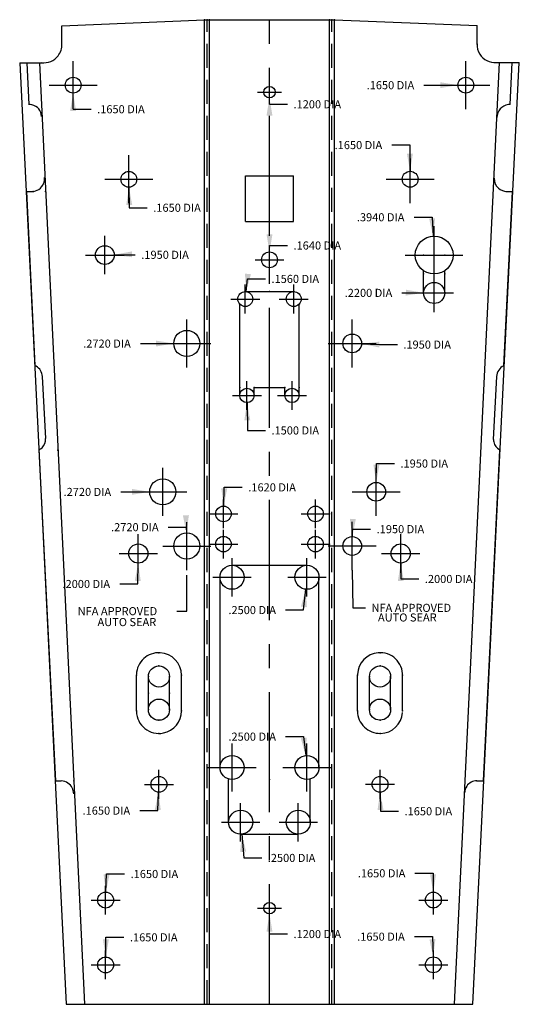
# Model space of a CAD drawing. Extents: x 2.7 to 7.9, y -3.4 to 6.9.
import ezdxf

# ---------------------------------------------------------------- set-up
doc = ezdxf.new("R2010")
doc.units = 0
doc.header["$MEASUREMENT"] = 0
doc.linetypes.add('CENTER', pattern=[2, 1.25, -0.25, 0.25, -0.25])
doc.linetypes.add('HIDDEN', pattern=[0.375, 0.25, -0.125])
doc.layers.add('DEFAULT', color=7, linetype='CONTINUOUS')
doc.styles.add('ARIAL', font='ARIAL.TTF')

msp = doc.modelspace()

# ---------------------------------------------------------------- linework, layer by layer
at = {"layer": 'DEFAULT'}
for p, q in [((3.0926, 6.8103), (4.5766, 6.8723)), ((4.577, 6.8728), (4.627, 6.8728)), ((4.577, -3.3772), (4.577, 6.8728)), ((4.627, 6.8728), (5.252, 6.8728)), ((4.627, -3.3772), (4.627, 6.8728)), ((5.252, 6.8728), (5.877, 6.8728)), ((5.877, 6.8728), (5.927, 6.8728)), ((5.877, -3.3772), (5.877, 6.8728)), ((5.927, -3.3772), (5.927, 6.8728)), ((5.9276, 6.8727), (7.4116, 6.8107)), ((3.0926, 6.6128), (3.0926, 6.8103)), ((7.4116, 6.6132), (7.4116, 6.8107)), ((2.6526, 6.4253), (3.1366, -3.3777)), ((2.6526, 6.4253), (2.7276, 6.4253)), ((2.7276, 6.4253), (2.8576, 6.4253)), ((2.7276, 6.4253), (2.7488, 5.9893)), ((2.8576, 6.4253), (3.3266, -3.3777)), ((2.8576, 6.4253), (2.9052, 6.4253)), ((3.2086, 6.1913), (3.2086, 6.4413)), ((7.1776, -3.3773), (7.6466, 6.4257)), ((7.2956, 6.1917), (7.2956, 6.4417)), ((7.3676, -3.3773), (7.8516, 6.4257)), ((7.599, 6.4257), (7.6466, 6.4257)), ((7.6466, 6.4257), (7.7766, 6.4257)), ((7.757, 5.9891), (7.7766, 6.4257)), ((7.7766, 6.4257), (7.8516, 6.4257)), ((2.9586, 6.1913), (3.2086, 6.1913)), ((3.2086, 6.1913), (3.4586, 6.1913)), ((3.2086, 5.9413), (3.2086, 6.1913)), ((5.252, 6.1178), (5.252, 6.2428)), ((6.8581, 6.1917), (7.0456, 6.1917)), ((7.0456, 6.1917), (7.2131, 6.1917)), ((7.0456, 6.1917), (7.2956, 6.1917)), ((7.2956, 5.9417), (7.2956, 6.1917)), ((7.2956, 6.1917), (7.5456, 6.1917)), ((3.2086, 5.9413), (3.2086, 6.1088)), ((5.127, 6.1178), (5.252, 6.1178)), ((5.2395, 6.1178), (5.252, 6.1178)), ((5.252, 5.9928), (5.252, 6.1178)), ((5.252, 6.1178), (5.377, 6.1178)), ((5.252, 5.9928), (5.252, 6.0578)), ((5.252, 5.9928), (5.4395, 5.9928)), ((3.2086, 5.9413), (3.3961, 5.9413)), ((6.525, 5.5684), (6.7125, 5.5684)), ((6.7125, 5.5684), (6.7149, 5.2941)), ((3.7886, 5.2113), (3.7886, 5.4613)), ((6.7156, 5.2117), (6.7156, 5.4617)), ((5.002, 5.2478), (5.252, 5.2478)), ((5.002, 4.7728), (5.002, 5.2478)), ((5.252, 5.2478), (5.502, 5.2478)), ((5.502, 4.7728), (5.502, 5.2478)), ((3.5386, 5.2113), (3.7886, 5.2113)), ((3.7886, 4.9613), (3.7886, 5.2113)), ((3.7886, 5.2113), (4.0386, 5.2113)), ((3.7897, 5.1289), (3.7927, 4.9157)), ((6.4656, 5.2117), (6.7156, 5.2117)), ((6.7156, 4.9617), (6.7156, 5.2117)), ((6.7156, 5.2117), (6.9656, 5.2117)), ((2.7221, 5.0827), (2.7939, 5.0827)), ((2.7221, 5.0827), (2.8089, 3.272)), ((7.6908, 3.2701), (7.7806, 5.0827)), ((7.7103, 5.0837), (7.7806, 5.0827)), ((3.7927, 4.9157), (3.9802, 4.9157)), ((5.002, 4.7728), (5.252, 4.7728)), ((5.252, 4.7728), (5.502, 4.7728)), ((6.7563, 4.8167), (6.9438, 4.8167)), ((6.9438, 4.8167), (6.9548, 4.6193)), ((6.9656, 4.4227), (6.9656, 4.7227)), ((3.5386, 4.4223), (3.5386, 4.6223)), ((5.252, 4.4548), (5.252, 4.5228)), ((5.252, 4.5228), (5.4395, 4.5228)), ((5.252, 4.3728), (5.252, 4.5228)), ((3.3386, 4.4223), (3.5386, 4.4223)), ((3.5386, 4.2223), (3.5386, 4.4223)), ((3.5386, 4.4223), (3.7386, 4.4223)), ((3.636, 4.4249), (3.6679, 4.4258)), ((3.6679, 4.4258), (3.8554, 4.4258)), ((6.6656, 4.4227), (6.9656, 4.4227)), ((6.9656, 4.4227), (7.2656, 4.4227)), ((6.9656, 4.1227), (6.9656, 4.4227)), ((5.102, 4.3728), (5.252, 4.3728)), ((5.252, 4.2228), (5.252, 4.3728)), ((5.252, 4.3728), (5.402, 4.3728)), ((6.8556, 4.0277), (6.8556, 4.2592)), ((6.9656, 4.0277), (6.9656, 4.2277)), ((7.0756, 4.0277), (7.0756, 4.2592)), ((5, 3.9648), (5, 4.1148)), ((5.0083, 4.0423), (5.0226, 4.1751)), ((5.0226, 4.1751), (5.2101, 4.1751)), ((5.504, 3.9648), (5.504, 4.1148)), ((5, 4.0428), (5.252, 4.0428)), ((5.252, 4.0428), (5.504, 4.0428)), ((6.6293, 4.0296), (6.8168, 4.0296)), ((6.7656, 4.0277), (6.9656, 4.0277)), ((6.8168, 4.0296), (6.8557, 4.0291)), ((6.9656, 3.8277), (6.9656, 4.0277)), ((6.9656, 4.0277), (7.1656, 4.0277)), ((4.85, 3.9648), (5, 3.9648)), ((4.9425, 3.0428), (4.9425, 3.912)), ((5, 3.8148), (5, 3.9648)), ((5, 3.9648), (5.15, 3.9648)), ((5.354, 3.9648), (5.504, 3.9648)), ((5.504, 3.8148), (5.504, 3.9648)), ((5.504, 3.9648), (5.654, 3.9648)), ((5.5615, 3.0428), (5.5615, 3.912)), ((4.3916, 3.5023), (4.3916, 3.7523)), ((6.1126, 3.5027), (6.1126, 3.7527)), ((3.9085, 3.5013), (4.096, 3.5013)), ((4.096, 3.5013), (4.2557, 3.5019)), ((4.1416, 3.5023), (4.3916, 3.5023)), ((4.3916, 3.2523), (4.3916, 3.5023)), ((4.3916, 3.5023), (4.6416, 3.5023)), ((5.8626, 3.5027), (6.1126, 3.5027)), ((6.1126, 3.2527), (6.1126, 3.5027)), ((6.1126, 3.5027), (6.3626, 3.5027)), ((6.21, 3.4987), (6.3951, 3.4911)), ((6.3951, 3.4911), (6.5826, 3.4911)), ((2.8881, 3.1583), (2.9216, 2.5121)), ((5.0175, 2.9608), (5.0175, 3.1108)), ((5.4865, 2.9608), (5.4865, 3.1108)), ((7.5824, 2.5037), (7.6161, 3.1578)), ((4.9425, 2.9608), (4.9425, 3.0428)), ((5.0925, 2.9608), (5.0925, 3.0428)), ((5.0925, 3.0428), (5.4115, 3.0428)), ((5.4115, 2.9608), (5.4115, 3.0428)), ((5.5615, 2.9608), (5.5615, 3.0428)), ((4.8675, 2.9608), (5.0175, 2.9608)), ((5.0175, 2.8108), (5.0175, 2.9608)), ((5.0175, 2.9608), (5.1675, 2.9608)), ((5.0185, 2.8859), (5.0226, 2.5974)), ((5.3365, 2.9608), (5.4865, 2.9608)), ((5.4865, 2.8108), (5.4865, 2.9608)), ((5.4865, 2.9608), (5.6365, 2.9608)), ((5.0226, 2.5974), (5.2101, 2.5974)), ((2.8521, 2.3937), (3.0251, -1.0523)), ((7.4776, -1.0523), (7.6476, 2.3907)), ((4.1416, 1.9573), (4.1416, 2.2073)), ((6.3626, 1.9577), (6.3626, 2.2077)), ((6.3633, 2.0551), (6.3648, 2.2528)), ((6.3648, 2.2528), (6.5523, 2.2528)), ((3.7041, 1.9573), (3.8916, 1.9573)), ((3.8916, 1.9573), (4.0056, 1.9573)), ((3.8916, 1.9573), (4.1416, 1.9573)), ((4.1416, 1.7073), (4.1416, 1.9573)), ((4.1416, 1.9573), (4.3916, 1.9573)), ((4.7755, 1.8087), (4.7816, 2.0047)), ((4.7816, 2.0047), (4.9691, 2.0047)), ((6.1126, 1.9577), (6.3626, 1.9577)), ((6.3626, 1.7077), (6.3626, 1.9577)), ((6.3626, 1.9577), (6.6126, 1.9577)), ((4.773, 1.7278), (4.773, 1.8778)), ((5.731, 1.7278), (5.731, 1.8778)), ((4.3916, 1.3933), (4.3916, 1.6433)), ((4.623, 1.7278), (4.773, 1.7278)), ((4.773, 1.5778), (4.773, 1.7278)), ((4.773, 1.7278), (4.923, 1.7278)), ((5.581, 1.7278), (5.731, 1.7278)), ((5.731, 1.5778), (5.731, 1.7278)), ((5.731, 1.7278), (5.881, 1.7278)), ((6.1126, 1.3937), (6.1126, 1.6437)), ((4.1983, 1.5905), (4.3858, 1.5905)), ((4.3858, 1.5905), (4.3877, 1.5292)), ((4.773, 1.4128), (4.773, 1.5628)), ((5.731, 1.4128), (5.731, 1.5628)), ((6.1149, 1.4911), (6.1169, 1.5694)), ((6.1169, 1.5694), (6.3044, 1.5694)), ((3.8866, 1.3153), (3.8866, 1.5153)), ((3.8866, 1.3153), (3.8866, 1.4653)), ((6.6176, 1.3157), (6.6176, 1.5157)), ((3.8866, 1.3153), (3.8866, 1.4153)), ((4.1416, 1.3933), (4.3916, 1.3933)), ((4.3916, 1.1433), (4.3916, 1.3933)), ((4.3916, 1.3933), (4.6416, 1.3933)), ((4.623, 1.4128), (4.773, 1.4128)), ((4.773, 1.2628), (4.773, 1.4128)), ((4.773, 1.4128), (4.923, 1.4128)), ((5.581, 1.4128), (5.731, 1.4128)), ((5.731, 1.2628), (5.731, 1.4128)), ((5.731, 1.4128), (5.881, 1.4128)), ((5.8626, 1.3937), (6.1126, 1.3937)), ((6.1126, 1.3937), (6.3626, 1.3937)), ((6.1126, 1.1437), (6.1126, 1.3937)), ((3.6866, 1.3153), (3.8866, 1.3153)), ((3.8866, 1.1653), (3.8866, 1.3153)), ((3.8866, 1.1153), (3.8866, 1.3153)), ((3.8866, 1.3153), (4.0866, 1.3153)), ((4.862, 1.0678), (4.862, 1.2678)), ((5.642, 1.0678), (5.642, 1.2678)), ((6.4176, 1.3157), (6.6176, 1.3157)), ((6.6176, 1.1157), (6.6176, 1.3157)), ((6.6176, 1.3157), (6.8176, 1.3157)), ((3.8804, 0.9989), (3.8847, 1.2154)), ((4.862, 1.1928), (5.252, 1.1928)), ((5.252, 1.1928), (5.6421, 1.1928)), ((6.1126, 1.1437), (6.1179, 0.7504)), ((6.618, 1.2158), (6.6188, 1.051)), ((4.3926, 0.716), (4.3926, 1.09)), ((4.662, 1.0678), (4.862, 1.0678)), ((4.737, -0.7572), (4.737, 1.0678)), ((4.862, 0.8678), (4.862, 1.0678)), ((4.862, 1.0678), (5.062, 1.0678)), ((5.442, 1.0678), (5.642, 1.0678)), ((5.642, 0.8678), (5.642, 1.0678)), ((5.642, 1.0678), (5.842, 1.0678)), ((5.767, -0.7572), (5.767, 1.0678)), ((6.6188, 1.051), (6.8063, 1.051)), ((3.6929, 0.9989), (3.8804, 0.9989)), ((5.607, 0.7275), (5.6293, 0.9435)), ((5.4195, 0.7275), (5.607, 0.7275)), ((6.1179, 0.7504), (6.2508, 0.7504)), ((4.2866, 0.716), (4.3926, 0.716)), ((3.8666, -0.3227), (3.8666, 0.0472)), ((3.9916, -0.3102), (3.9916, 0.0348)), ((4.2116, -0.3102), (4.2116, 0.0346)), ((4.3366, -0.3227), (4.3366, 0.0472)), ((6.1676, -0.3223), (6.1676, 0.0476)), ((6.2926, -0.3098), (6.2927, 0.035)), ((6.5126, -0.3098), (6.5126, 0.035)), ((6.6376, -0.3223), (6.6376, 0.0477)), ((5.4195, -0.5904), (5.607, -0.5904)), ((5.607, -0.5904), (5.6285, -0.788)), ((4.862, -0.9122), (4.862, -0.6622)), ((5.642, -0.9122), (5.642, -0.6622)), ((4.737, -0.9122), (4.737, -0.7572)), ((5.767, -0.9122), (5.767, -0.7572)), ((4.612, -0.9122), (4.862, -0.9122)), ((4.862, -1.1622), (4.862, -0.9122)), ((4.862, -0.9122), (5.112, -0.9122)), ((5.392, -0.9122), (5.642, -0.9122)), ((5.642, -1.1622), (5.642, -0.9122)), ((5.642, -0.9122), (5.892, -0.9122)), ((4.1016, -1.0877), (4.1016, -0.9377)), ((6.4026, -1.0873), (6.4026, -0.9373)), ((3.0251, -1.0523), (3.0856, -1.0526)), ((3.9516, -1.0877), (4.1016, -1.0877)), ((4.1016, -1.2377), (4.1016, -1.0877)), ((4.1016, -1.0877), (4.2516, -1.0877)), ((4.827, -1.4822), (4.827, -1.0372)), ((5.677, -1.4822), (5.677, -1.0372)), ((6.2526, -1.0873), (6.4026, -1.0873)), ((6.4026, -1.2373), (6.4026, -1.0873)), ((6.4026, -1.0873), (6.5526, -1.0873)), ((7.4076, -1.0523), (7.4776, -1.0523)), ((4.0893, -1.3607), (4.0979, -1.1701)), ((6.4041, -1.1697), (6.4077, -1.3671)), ((4.952, -1.4822), (4.952, -1.2822)), ((5.552, -1.4822), (5.552, -1.2822)), ((3.9018, -1.3607), (4.0893, -1.3607)), ((6.4077, -1.3671), (6.5952, -1.3671)), ((4.752, -1.4822), (4.952, -1.4822)), ((4.952, -1.6822), (4.952, -1.4822)), ((4.952, -1.4822), (5.152, -1.4822)), ((5.352, -1.4822), (5.552, -1.4822)), ((5.552, -1.6822), (5.552, -1.4822)), ((5.552, -1.4822), (5.752, -1.4822)), ((4.952, -1.6072), (5.252, -1.6072)), ((4.9627, -1.6067), (4.9841, -1.853)), ((5.252, -1.6072), (5.552, -1.6072)), ((4.9841, -1.853), (5.1716, -1.853)), ((3.5496, -2.2103), (3.5568, -2.0203)), ((3.5568, -2.0203), (3.7443, -2.0203)), ((6.7661, -2.0131), (6.9536, -2.0131)), ((6.9536, -2.0131), (6.9565, -2.2099)), ((3.5466, -2.2927), (3.5466, -2.1427)), ((6.9576, -2.2923), (6.9576, -2.1423)), ((5.252, -2.3772), (5.252, -2.2522)), ((3.3966, -2.2927), (3.5466, -2.2927)), ((3.5466, -2.4427), (3.5466, -2.2927)), ((3.5466, -2.2927), (3.6966, -2.2927)), ((6.8076, -2.2923), (6.9576, -2.2923)), ((6.9576, -2.4423), (6.9576, -2.2923)), ((6.9576, -2.2923), (7.1076, -2.2923)), ((5.127, -2.3772), (5.252, -2.3772)), ((5.2518, -2.6454), (5.252, -2.4371)), ((5.252, -2.5022), (5.252, -2.3772)), ((5.252, -2.3772), (5.377, -2.3772)), ((5.2518, -2.6454), (5.4393, -2.6454)), ((3.5476, -2.8853), (3.5501, -2.6799)), ((3.5501, -2.6799), (3.7376, -2.6799)), ((6.7594, -2.6727), (6.9469, -2.6727)), ((6.9469, -2.6727), (6.9547, -2.8849)), ((3.5466, -2.9677), (3.5466, -2.8177)), ((6.9576, -2.9673), (6.9576, -2.8173)), ((3.3966, -2.9677), (3.5466, -2.9677)), ((3.5466, -3.1177), (3.5466, -2.9677)), ((3.5466, -2.9677), (3.6966, -2.9677)), ((6.8076, -2.9673), (6.9576, -2.9673)), ((6.9576, -3.1173), (6.9576, -2.9673)), ((6.9576, -2.9673), (7.1076, -2.9673)), ((3.1366, -3.3777), (3.1366, -3.3761)), ((3.1366, -3.3777), (3.3266, -3.3777)), ((3.2116, -3.3777), (3.3266, -3.3777)), ((3.3266, -3.3777), (4.5766, -3.3777)), ((4.577, -3.3772), (4.627, -3.3772)), ((4.627, -3.3772), (5.252, -3.3772)), ((5.252, -3.3772), (5.877, -3.3772)), ((5.877, -3.3772), (5.927, -3.3772)), ((5.9276, -3.3773), (7.1776, -3.3773)), ((7.1776, -3.3773), (7.2926, -3.3773)), ((7.1776, -3.3773), (7.3676, -3.3773))]:
    msp.add_line(p, q, dxfattribs=at)
at = {"layer": 'DEFAULT', "linetype": 'HIDDEN'}
for p, q in [((4.602, -3.3772), (4.602, 6.8728)), ((5.902, -3.3772), (5.902, 6.8728))]:
    msp.add_line(p, q, dxfattribs=at)
at = {"layer": 'DEFAULT', "linetype": 'CENTER'}
msp.add_line((5.252, -3.3772), (5.252, 6.8728), dxfattribs=at)
at = {"layer": 'DEFAULT'}
for centre, radius in [((3.2086, 6.1913), 0.0825), ((7.2956, 6.1917), 0.0825), ((5.252, 6.1178), 0.06), ((3.7886, 5.2113), 0.0825), ((6.7156, 5.2117), 0.0825), ((6.9656, 4.4227), 0.197), ((3.5386, 4.4223), 0.0975), ((5.252, 4.3728), 0.082), ((6.9656, 4.0277), 0.11), ((5, 3.9648), 0.078), ((5.504, 3.9648), 0.078), ((4.3916, 3.5023), 0.136), ((6.1126, 3.5027), 0.0975), ((5.0175, 2.9608), 0.075), ((5.4865, 2.9608), 0.075), ((4.1416, 1.9573), 0.136), ((6.3626, 1.9577), 0.0975), ((4.773, 1.7278), 0.081), ((5.731, 1.7278), 0.081), ((4.3916, 1.3933), 0.136), ((4.773, 1.4128), 0.081), ((5.731, 1.4128), 0.081), ((6.1126, 1.3937), 0.0975), ((3.8866, 1.3153), 0.1), ((6.6176, 1.3157), 0.1), ((4.862, 1.0678), 0.125), ((5.642, 1.0678), 0.125), ((4.1016, 0.0348), 0.11), ((6.4026, 0.0352), 0.11), ((4.1016, -0.3102), 0.11), ((6.4026, -0.3098), 0.11), ((4.862, -0.9122), 0.125), ((5.642, -0.9122), 0.125), ((4.1016, -1.0877), 0.0825), ((6.4026, -1.0873), 0.0825), ((4.952, -1.4822), 0.125), ((5.552, -1.4822), 0.125), ((3.5466, -2.2927), 0.0825), ((6.9576, -2.2923), 0.0825), ((5.252, -2.3772), 0.06), ((3.5466, -2.9677), 0.0825), ((6.9576, -2.9673), 0.0825)]:
    msp.add_circle(centre, radius, dxfattribs=at)
for centre, radius, start, end in [((2.9051, 6.6128), 0.1875, 321.3259, 2.2014), ((7.5991, 6.6132), 0.1875, 177.9513, 211.8498), ((2.9051, 6.6128), 0.1875, 262.4276, 321.3259), ((7.5991, 6.6132), 0.1875, 211.8498, 273.9157), ((2.7538, 5.8643), 0.125, 77.8444, 93.7165), ((2.7538, 5.8643), 0.125, 0.8257, 77.8444), ((7.754, 5.8521), 0.137, 96.7098, 179.4978), ((7.754, 5.8521), 0.137, 88.8283, 96.7098), ((2.7751, 5.2197), 0.137, 336.9168, 4.187), ((2.7751, 5.2197), 0.137, 271.7154, 336.9168), ((7.7276, 5.2197), 0.137, 179.2467, 227.2197), ((7.7276, 5.2197), 0.137, 227.2197, 267.7395), ((2.7632, 3.1557), 0.125, 61.2394, 68.5477), ((2.7632, 3.1557), 0.125, 1.1925, 61.2394), ((7.741, 3.1557), 0.125, 113.6924, 179.0368), ((2.7968, 2.5057), 0.125, 314.7405, 2.9357), ((7.7073, 2.5057), 0.125, 180.9174, 193.4244), ((7.7073, 2.5057), 0.125, 193.4244, 241.6713), ((2.7968, 2.5057), 0.125, 296.2779, 314.7405), ((4.1016, 0.0473), 0.235, 87.1218, 177.4384), ((4.1016, 0.0473), 0.235, 0.3171, 87.1218), ((6.4026, 0.0477), 0.235, 94.6867, 177.7805), ((6.4026, 0.0477), 0.235, 358.7075, 94.6867), ((6.4026, -0.3223), 0.235, 91.0487, 91.0731), ((4.1016, -0.3227), 0.235, 181.4876, 281.3147), ((4.1016, -0.3227), 0.235, 281.3147, 359.6097), ((6.4026, -0.3223), 0.235, 180.7805, 271.0487), ((6.4026, -0.3223), 0.235, 271.0487, 355.6798), ((4.862, -0.7572), 0.125, 40.064, 40.3575), ((3.0781, -1.1893), 0.137, 55.8922, 86.8596), ((3.0781, -1.1893), 0.137, 0.7951, 55.8922), ((7.4076, -1.1773), 0.125, 145.801, 179.1285), ((7.4076, -1.1773), 0.125, 88.349, 145.801)]:
    msp.add_arc(centre, radius, start, end, dxfattribs=at)
at = {"layer": 'DEFAULT', "color": 1}
for p in [(4.577, 6.8728), (4.602, 6.8728), (4.602, 6.8728), (4.627, 6.8728), (5.877, 6.8728), (5.902, 6.8728), (5.927, 6.8728), (3.2086, 6.1913), (7.2956, 6.1917), (5.252, 6.1178), (5.252, 5.2478), (5.252, 5.2478), (3.7886, 5.2113), (6.7156, 5.2117), (2.7939, 5.0827), (2.9221, 5.0827), (5.252, 4.7728), (3.5386, 4.4223), (6.8556, 4.4227), (6.9656, 4.4227), (7.0756, 4.4227), (5.252, 4.3728), (6.8556, 4.2277), (7.0756, 4.2277), (5, 4.0428), (5.252, 4.0428), (5.504, 4.0428), (6.8556, 4.0277), (6.9656, 4.0277), (7.0756, 4.0277), (5, 3.9648), (5.504, 3.9648), (4.3916, 3.5023), (6.1126, 3.5027), (4.9425, 3.0428), (5.0925, 3.0428), (5.252, 3.0428), (5.4115, 3.0428), (5.5615, 3.0428), (4.9425, 2.9608), (5.0175, 2.9608), (5.0925, 2.9608), (5.4115, 2.9608), (5.4865, 2.9608), (5.5615, 2.9608), (3.0501, 2.3907), (4.1416, 1.9573), (6.3626, 1.9577), (4.773, 1.7278), (5.731, 1.7278), (5.877, 1.7278), (4.3916, 1.3933), (4.773, 1.4128), (5.731, 1.4128), (5.877, 1.4128), (5.877, 1.4128), (6.1126, 1.3937), (3.8866, 1.3153), (6.6176, 1.3157), (5.252, 1.1928), (4.862, 1.0678), (5.642, 1.0678), (4.1016, 0.2823), (6.4026, 0.2827), (4.1016, 0.1448), (6.4026, 0.1452), (3.8666, 0.0473), (3.9916, 0.0348), (4.2116, 0.0348), (4.3366, 0.0473), (6.1676, 0.0477), (6.2926, 0.0352), (6.5126, 0.0352), (6.6376, 0.0477), (3.9916, -0.1377), (4.2116, -0.1377), (3.8666, -0.3227), (3.9916, -0.3102), (4.2116, -0.3102), (4.3366, -0.3227), (6.1676, -0.3223), (6.2926, -0.3098), (6.5126, -0.3098), (6.6376, -0.3223), (4.1016, -0.4202), (6.4026, -0.4198), (4.1016, -0.5577), (4.1016, -0.5577), (6.4026, -0.5573), (4.862, -0.9122), (5.642, -0.9122), (3.2151, -1.0523), (4.1016, -1.0877), (5.252, -1.0372), (6.4026, -1.0873), (4.952, -1.4822), (5.552, -1.4822), (5.252, -1.6072), (3.5466, -2.2927), (6.9576, -2.2923), (5.252, -2.3772), (3.5466, -2.9677), (6.9576, -2.9673), (4.577, -3.3772), (4.602, -3.3772), (4.627, -3.3772), (5.252, -3.3772), (5.877, -3.3772), (5.902, -3.3772), (5.927, -3.3772), (7.1776, -3.3773)]:
    msp.add_point(p, dxfattribs=at)
at = {"layer": 'DEFAULT'}
for points in [[(7.0282, 6.1611), (7.0282, 6.2222), (7.2131, 6.1917)], [(3.2396, 5.9239), (3.1775, 5.9239), (3.2086, 6.1088)], [(5.283, 5.8729), (5.2209, 5.8729), (5.252, 6.0578)], [(6.6822, 5.4786), (6.7444, 5.4792), (6.7149, 5.2941)], [(3.8233, 4.9444), (3.7611, 4.9436), (3.7897, 5.1289)], [(6.9135, 4.8021), (6.9755, 4.8055), (6.9548, 4.6193)], [(5.2209, 4.6396), (5.283, 4.6396), (5.252, 4.4548)], [(3.8198, 4.4605), (3.8216, 4.3995), (3.636, 4.4249)], [(4.997, 4.2293), (5.0588, 4.2228), (5.0083, 4.0423)], [(6.6704, 4.0007), (6.6712, 4.0618), (6.8557, 4.0291)], [(4.0709, 3.4707), (4.0707, 3.5318), (4.2557, 3.5019)], [(6.3959, 3.5215), (6.3933, 3.4605), (6.21, 3.4987)], [(5.0521, 2.7014), (4.9899, 2.7006), (5.0185, 2.8859)], [(6.3334, 2.2401), (6.3956, 2.2397), (6.3633, 2.0551)], [(3.8207, 1.9267), (3.8207, 1.9878), (4.0056, 1.9573)], [(4.7501, 1.9943), (4.8122, 1.9925), (4.7755, 1.8087)], [(4.3512, 1.713), (4.4133, 1.7148), (4.3877, 1.5292)], [(6.0882, 1.6765), (6.1504, 1.6751), (6.1149, 1.4911)], [(3.9123, 1.0299), (3.8501, 1.0311), (3.8847, 1.2154)], [(6.6499, 1.031), (6.5878, 1.0308), (6.618, 1.2158)], [(5.6412, 0.7565), (5.5794, 0.7627), (5.6293, 0.9435)], [(5.5776, -0.6075), (5.6394, -0.6009), (5.6285, -0.788)], [(4.1205, -1.3561), (4.0584, -1.3533), (4.0979, -1.1701)], [(6.4383, -1.354), (6.3761, -1.355), (6.4041, -1.1697)], [(5.0094, -1.7882), (4.9475, -1.7934), (4.9627, -1.6067)], [(3.5252, -2.0244), (3.5873, -2.0266), (3.5496, -2.2103)], [(6.9228, -2.0254), (6.985, -2.0246), (6.9565, -2.2099)], [(5.283, -2.6219), (5.2209, -2.6219), (5.252, -2.4371)], [(3.5186, -2.7), (3.5808, -2.7008), (3.5476, -2.8853)], [(6.9169, -2.7012), (6.979, -2.699), (6.9547, -2.8849)]]:
    msp.add_solid(points, dxfattribs=at)

# ---------------------------------------------------------------- texts
at = {"layer": 'DEFAULT', "style": 'ARIAL'}
for s, p in [('.1650 DIA', (6.2631, 6.1488)), ('.1650 DIA', (3.4586, 5.8984)), ('.1200 DIA', (5.502, 5.9499)), ('.1650 DIA', (5.93, 5.5255)), ('.1650 DIA', (4.0427, 4.8728)), ('.3940 DIA', (6.1613, 4.7738)), ('.1640 DIA', (5.502, 4.4799)), ('.1950 DIA', (3.9179, 4.3829)), ('.1560 DIA', (5.2726, 4.1322)), ('.2200 DIA', (6.0343, 3.9867)), ('.2720 DIA', (3.3135, 3.4584)), ('.1950 DIA', (6.6451, 3.4482)), ('.1500 DIA', (5.2726, 2.5545)), ('.1950 DIA', (6.6148, 2.2099)), ('.2720 DIA', (3.1091, 1.9144)), ('.1620 DIA', (5.0316, 1.9618)), ('.2720 DIA', (3.6033, 1.5476)), ('.1950 DIA', (6.3669, 1.5265)), ('.2000 DIA', (3.0979, 0.956)), ('.2000 DIA', (6.8688, 1.0081)), ('NFA APPROVED ', (3.2556, 0.6731)), ('.2500 DIA', (4.8245, 0.6846)), ('NFA APPROVED', (6.3133, 0.7075)), ('.2500 DIA', (4.8245, -0.6333)), ('.1650 DIA', (3.3068, -1.4036)), ('.1650 DIA', (6.6577, -1.41)), ('.2500 DIA', (5.2341, -1.8959)), ('.1650 DIA', (3.8068, -2.0632)), ('.1650 DIA', (6.1711, -2.056)), ('.1650 DIA', (3.8001, -2.7228)), ('.1200 DIA', (5.5018, -2.6883)), ('.1650 DIA', (6.1644, -2.7156))]:
    msp.add_text(s, height=0.0842, dxfattribs=at).set_placement(p)
for p in [(3.4625, 0.5596), (6.3807, 0.6076)]:
    msp.add_text('AUTO SEAR', height=0.0842, rotation=360, dxfattribs=at).set_placement(p)

doc.saveas('drawing.dxf')
